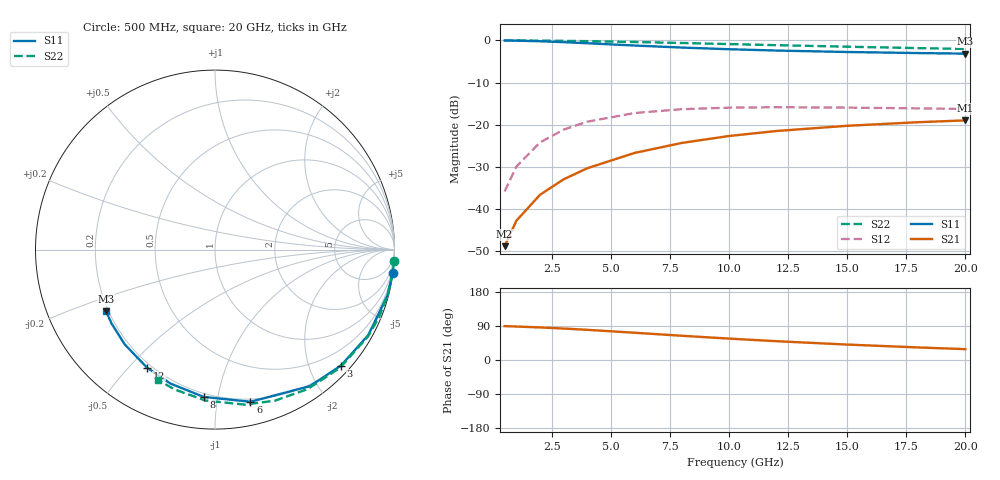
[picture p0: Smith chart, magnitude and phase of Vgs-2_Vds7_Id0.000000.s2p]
# Hz S RI R 50
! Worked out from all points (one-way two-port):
!   12 points, 500 MHz to 20 GHz, reference 50 ohm
!   highest |S21| = -18.97 dB at 20 GHz (marker M1); lowest = -48.8 dB at 500 MHz (marker M2)
!   lowest |S11| = -3.1 dB at 20 GHz (marker M3), VSWR 5.61, Z = 9.51 - j12.7 ohm
!   |S11| at or under -10 dB: nowhere
!   |S22| runs from -2.0 to 0.0 dB; largest |S21 - S12| = 0.12
!   S11 on the Smith chart (normalised r, x): 500 MHz: 0, -15; 3 GHz: 0.18, -2.55; 6 GHz: 0.18, -1.24; 8 GHz: 0.18, -0.91; 12 GHz: 0.18, -0.56; 20 GHz: 0.19, -0.25
5e8  0.9901 -0.1292  3.33e-05 0.00362  0.00153 0.0161  0.9975 -0.0657
1e9  0.9611 -0.2541  0.000217 0.00727  0.006 0.0314  0.9901 -0.131
2e9  0.8539 -0.4765  0.00106 0.0147  0.0224 0.0575  0.9609 -0.2578
3e9  0.7011 -0.6471  0.00274 0.0223  0.0451 0.075  0.914 -0.3766
4e9  0.5283 -0.761  0.0055 0.03  0.0698 0.0832  0.8519 -0.4848
6e9  0.1976 -0.8477  0.0144 0.044  0.1129 0.0787  0.6951 -0.66
8e9  -0.0628 -0.8208  0.0267 0.0546  0.1407 0.0598  0.5151 -0.7776
1e10  -0.2489 -0.7461  0.0406 0.0612  0.1548 0.0382  0.3341 -0.8418
1.2e10  -0.3786 -0.6577  0.0545 0.0642  0.1602 0.0188  0.165 -0.8635
1.5e10  -0.5033 -0.5277  0.0736 0.0633  0.1596 -0.0037  -0.0527 -0.841
1.8e10  -0.5763 -0.4117  0.0897 0.0585  0.1551 -0.0194  -0.2244 -0.7795
2e10  -0.6073 -0.3429  0.0988 0.054  0.1515 -0.0272  -0.3158 -0.7273
